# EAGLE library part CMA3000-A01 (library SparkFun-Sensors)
3-axis 2/8g analog output accelerometer

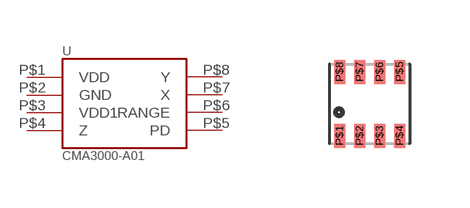
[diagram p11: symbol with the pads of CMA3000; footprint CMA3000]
Designator prefix -

## CMA3000-A01  [CMA3000]
P$1  VDD
P$2  GND
P$3  VDD1
P$4  Z
P$5  PD
P$6  RANGE
P$7  X
P$8  Y

## Footprint CMA3000 (pad centres in mm)
smd 0.275 x 0.6: P$1 -0.75,-0.8; P$2 -0.25,-0.8; P$3 0.25,-0.8; P$4 0.75,-0.8; P$5 0.75,0.8; P$6 0.25,0.8; P$7 -0.25,0.8; P$8 -0.75,0.8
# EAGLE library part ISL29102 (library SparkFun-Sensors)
Light-to-voltage converter.

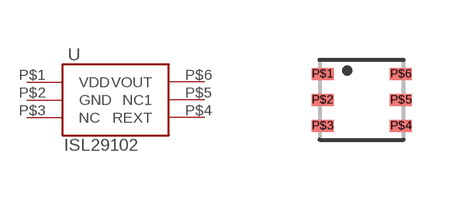
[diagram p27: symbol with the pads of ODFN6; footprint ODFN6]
Designator prefix -

## ISL29102  [ODFN6]
P$1  VDD
P$2  GND
P$3  NC
P$4  REXT
P$5  NC1
P$6  VOUT

## Footprint ODFN6 (pad centres in mm)
smd 0.55 x 0.3: P$1 -0.98,0.65; P$2 -0.98,0; P$3 -0.98,-0.65; P$4 0.98,-0.65; P$5 0.98,0; P$6 0.98,0.65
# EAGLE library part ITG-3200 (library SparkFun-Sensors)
ITG-3200 3-axis gyro, digital output, qfn24 package

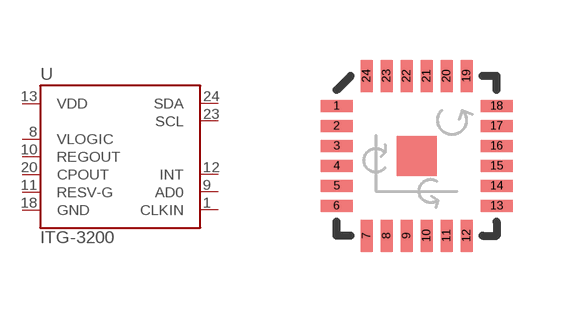
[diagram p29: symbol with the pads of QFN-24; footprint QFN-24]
Designator prefix U

## ITG-3200  [QFN-24]
1  CLKIN
8  VLOGIC
9  AD0
10  REGOUT
11  RESV-G
12  INT
13  VDD
18  GND
20  CPOUT
23  SCL
24  SDA

## Footprint QFN-24 (pad centres in mm)
smd 0.8 x 0.3: 1 -2,1.25; 2 -2,0.75; 3 -2,0.25; 4 -2,-0.25; 5 -2,-0.75; 6 -2,-1.25; 13 2,-1.25; 14 2,-0.75; 15 2,-0.25; 16 2,0.25; 17 2,0.75; 18 2,1.25
smd 0.3 x 0.8: 7 -1.25,-2; 8 -0.75,-2; 9 -0.25,-2; 10 0.25,-2; 11 0.75,-2; 12 1.25,-2; 19 1.25,2; 20 0.75,2; 21 0.25,2; 22 -0.25,2; 23 -0.75,2; 24 -1.25,2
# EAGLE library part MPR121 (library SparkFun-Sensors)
MPR121 Capacitive Touch Sensor Controller

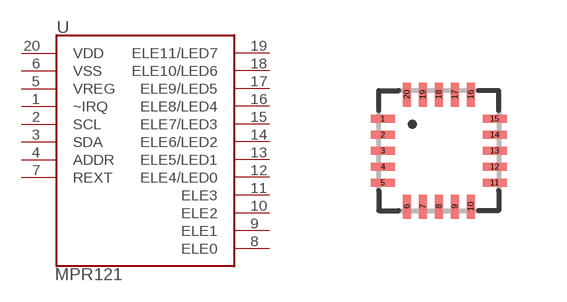
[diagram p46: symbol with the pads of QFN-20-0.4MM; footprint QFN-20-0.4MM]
Designator prefix -

## MPR121QFN20  [QFN-20-0.4MM]
1  ~IRQ
2  SCL
3  SDA
4  ADDR
5  VREG
6  VSS
7  REXT
8  ELE0
9  ELE1
10  ELE2
11  ELE3
12  ELE4/LED0
13  ELE5/LED1
14  ELE6/LED2
15  ELE7/LED3
16  ELE8/LED4
17  ELE9/LED5
18  ELE10/LED6
19  ELE11/LED7
20  VDD

## Footprint QFN-20-0.4MM (pad centres in mm)
** 20-pin QFN ** initially designed for MPR121 | 0.4mm pitch | 3x3x0.65mm | ** VERY UNPROVEN **
smd 0.6 x 0.2: 1 -1.4,0.8; 2 -1.4,0.4; 3 -1.4,0; 4 -1.4,-0.4; 5 -1.4,-0.8; 11 1.4,-0.8; 12 1.4,-0.4; 13 1.4,0; 14 1.4,0.4; 15 1.4,0.8
smd 0.2 x 0.6: 6 -0.8,-1.4; 7 -0.4,-1.4; 8 0,-1.4; 9 0.4,-1.4; 10 0.8,-1.4; 16 0.8,1.4; 17 0.4,1.4; 18 0,1.4; 19 -0.4,1.4; 20 -0.8,1.4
